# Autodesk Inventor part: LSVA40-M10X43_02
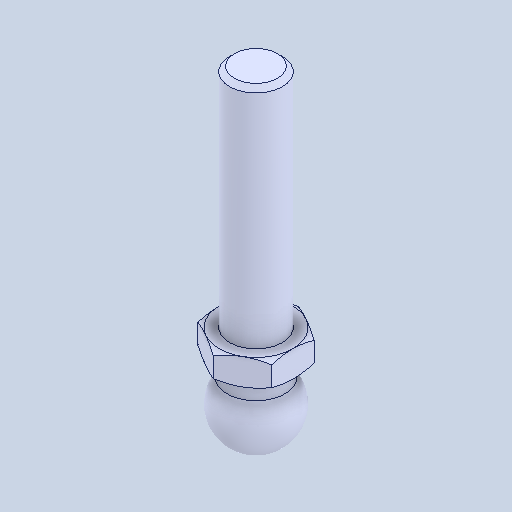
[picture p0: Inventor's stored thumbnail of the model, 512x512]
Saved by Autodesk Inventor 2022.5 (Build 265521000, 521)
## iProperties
Created: 2024-08
Part Number: LSVA40-M10X43_02
Material: 一般
Document SubType Name: Modeling
Designer: ImaoCorp
Density: 1 g/cm^3
Appearance: 既定
Author: ImaoCorp
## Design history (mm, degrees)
feature "LSVA40-M10X43_02"
node "ソリッド1"
